VERSION 5.7 ;
  NOWIREEXTENSIONATPIN ON ;
  DIVIDERCHAR "/" ;
  BUSBITCHARS "[]" ;
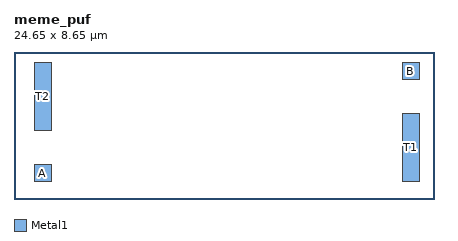
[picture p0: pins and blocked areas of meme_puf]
MACRO meme_puf
  CLASS BLOCK ;
  FOREIGN meme_puf ;
  ORIGIN 0.000 0.000 ;
  SIZE 24.650 BY 8.650 ;
  PIN A
    DIRECTION INOUT ;
    USE ANALOG ;
    PORT
      LAYER Metal1 ;
        RECT 1.200 1.000 2.200 2.000 ;
    END
  END A
  PIN T1
    DIRECTION INOUT ;
    USE ANALOG ;
    PORT
      LAYER Metal1 ;
        RECT 22.800 1.000 23.800 5.000 ;
    END
  END T1
  PIN T2
    DIRECTION INOUT ;
    USE ANALOG ;
    PORT
      LAYER Metal1 ;
        RECT 1.200 4.000 2.200 8.000 ;
    END
  END T2
  PIN B
    DIRECTION INOUT ;
    USE ANALOG ;
    PORT
      LAYER Metal1 ;
        RECT 22.800 7.000 23.800 8.000 ;
    END
  END B
END meme_puf
END LIBRARY
